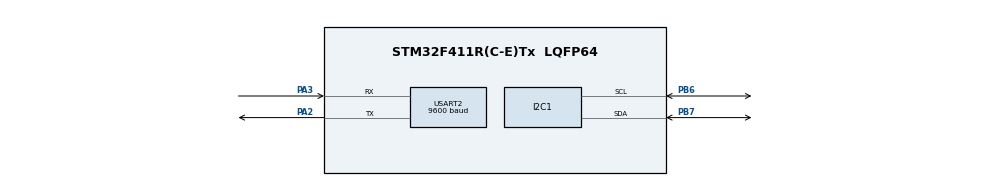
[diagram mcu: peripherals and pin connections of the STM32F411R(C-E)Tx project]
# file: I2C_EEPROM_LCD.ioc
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Mcu.Family=STM32F4
Mcu.Name=STM32F411R(C-E)Tx
Mcu.Package=LQFP64
NVIC.PriorityGroup=NVIC_PRIORITYGROUP_0
NVIC.USART2_IRQn=true\:0\:0\:false\:false\:true\:true\:true\:true
PA2.Mode=Asynchronous
PA2.Signal=USART2_TX
PA3.Mode=Asynchronous
PA3.Signal=USART2_RX
PB6.Mode=I2C
PB6.Signal=I2C1_SCL
PB7.Mode=I2C
PB7.Signal=I2C1_SDA
ProjectManager.HeapSize=0x200
ProjectManager.StackSize=0x400
ProjectManager.TargetToolchain=STM32CubeIDE
RCC.48MHZClocksFreq_Value=84000000
RCC.AHBFreq_Value=16000000
RCC.APB1CLKDivider=RCC_HCLK_DIV2
RCC.APB1Freq_Value=8000000
RCC.APB1TimFreq_Value=16000000
RCC.APB2Freq_Value=16000000
RCC.APB2TimFreq_Value=16000000
RCC.CortexFreq_Value=16000000
RCC.FLatency-AdvancedSettings=FLASH_LATENCY_0
RCC.HCLKFreq_Value=16000000
RCC.HSE_VALUE=8000000
RCC.HSI_VALUE=16000000
RCC.LSE_VALUE=32768
RCC.PLLN=336
RCC.PLLP=RCC_PLLP_DIV4
RCC.SYSCLKFreq_VALUE=16000000
RCC.VCOOutputFreq_Value=336000000
USART2.BaudRate=9600
USART2.VirtualMode=VM_ASYNC
board=NUCLEO-F411RE

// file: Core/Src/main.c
/* USER CODE BEGIN Header */
/**
  **************************
  * @file           : main.c
  * @brief          : Main program body
  **************************
  * @attention
  *
  * Copyright (c) 2022 STMicroelectronics.
  * All rights reserved.
  *
  * This software is licensed under terms that can be found in the LICENSE file
  * in the root directory of this software component.
  * If no LICENSE file comes with this software, it is provided AS-IS.
  *
  **************************
  */
/* USER CODE END Header */
#include "main.h"
#include <string.h>
#include"lcd.h"

I2C_HandleTypeDef hi2c1;

UART_HandleTypeDef huart2;

void SystemClock_Config(void);
static void MX_GPIO_Init(void);
static void MX_I2C1_Init(void);
static void MX_USART2_UART_Init(void);

uint8_t Rcvd_Data;
uint8_t Data_Buffer[8];
uint8_t i;
uint8_t USER_DATA[8] ="sandeep!";
uint8_t sentbit;

int main(void)
{

  /* MCU Configuration--------------------------------------------------------*/

  /* Reset of all peripherals, Initializes the Flash interface and the Systick. */
  HAL_Init();

  /* Configure the system clock */
  SystemClock_Config();

  /* Initialize all configured peripherals */
  MX_GPIO_Init();
  MX_I2C1_Init();
  MX_USART2_UART_Init();
  uint32_t count = 0;
  /* USER CODE BEGIN 2 */

	LCD_init();
	delay(10);

  HAL_UART_Transmit(&huart2, (uint8_t *)USER_DATA, strlen(USER_DATA), HAL_MAX_DELAY);
  /* USER CODE END 2 */
  /* Infinite loop */
  /* USER CODE BEGIN WHILE */
//  while (USER_DATA[i]!='\0')
//  {
//    /* USER CODE END WHILE */
//	  sentbit=USER_DATA[i];
//	  i++;
//	  HAL_I2C_Mem_Write(&hi2c1, 0xA0, 0, 0xFF, &sentbit, 1, 10);
//	  HAL_Delay(100);
//	  HAL_I2C_Mem_Read(&hi2c1, 0xA0, 0, 0xFF, &Rcvd_Data, 1, 10);
//	  Data_Buffer[count++] = Rcvd_Data;
//    /* USER CODE BEGIN 3 */
//  }

	while(1)
	{
		HAL_UART_Receive(&huart2, &Rcvd_Data, 1, HAL_MAX_DELAY);    //Read byte by byte

		if(Rcvd_Data == '\r')
		{
			//detect Return/Enter key
			Data_Buffer[count++] = '\r';
			break;
		}
		else
		{
			Data_Buffer[count++] = Rcvd_Data;
		}
	}

    HAL_UART_Transmit(&huart2, (uint8_t*)Data_Buffer, count, HAL_MAX_DELAY);
	i=0;
	count=0;
	while (Data_Buffer[i]!='\0')
	{
	  /* USER CODE END WHILE */
		sentbit=Data_Buffer[i];
//		i++;
		HAL_I2C_Mem_Write(&hi2c1, 0xA0, 0, 0xFF, &sentbit, 1, 10);
		HAL_Delay(100);
		HAL_I2C_Mem_Read(&hi2c1, 0xA0, 0, 0xFF, &Rcvd_Data, 1, 10);
		Data_Buffer[count++] = Rcvd_Data;
		USER_DATA[i]=Rcvd_Data;
		i=i+1;
	  /* USER CODE BEGIN 3 */
	}

	  char str[8];
	  LCD_string("AT24C32INTERFACE");
	  HAL_Delay(1000);
	  LCD_command(1);
	  LCD_string("DATA WRITE");
	  LCD_command(0xC4);
	  strcpy(str,Data_Buffer);
	  LCD_string(str);
	  HAL_Delay(1000);
	  LCD_command(1);
	  LCD_string("DATA READ");
	  LCD_command(0xC4);
	  strcpy(str,USER_DATA);
	  LCD_string(str);
	  delay(500);
  /* USER CODE END 3 */
}

void SystemClock_Config(void)
{
  RCC_OscInitTypeDef RCC_OscInitStruct = {0};
  RCC_ClkInitTypeDef RCC_ClkInitStruct = {0};

  /** Configure the main internal regulator output voltage
  */
  __HAL_RCC_PWR_CLK_ENABLE();
  __HAL_PWR_VOLTAGESCALING_CONFIG(PWR_REGULATOR_VOLTAGE_SCALE1);

  /** Initializes the RCC Oscillators according to the specified parameters
  * in the RCC_OscInitTypeDef structure.
  */
  RCC_OscInitStruct.OscillatorType = RCC_OSCILLATORTYPE_HSI;
  RCC_OscInitStruct.HSIState = RCC_HSI_ON;
  RCC_OscInitStruct.HSICalibrationValue = RCC_HSICALIBRATION_DEFAULT;
  RCC_OscInitStruct.PLL.PLLState = RCC_PLL_NONE;
  if (HAL_RCC_OscConfig(&RCC_OscInitStruct) != HAL_OK)
  {
    Error_Handler();
  }

  /** Initializes the CPU, AHB and APB buses clocks
  */
  RCC_ClkInitStruct.ClockType = RCC_CLOCKTYPE_HCLK|RCC_CLOCKTYPE_SYSCLK
                              |RCC_CLOCKTYPE_PCLK1|RCC_CLOCKTYPE_PCLK2;
  RCC_ClkInitStruct.SYSCLKSource = RCC_SYSCLKSOURCE_HSI;
  RCC_ClkInitStruct.AHBCLKDivider = RCC_SYSCLK_DIV1;
  RCC_ClkInitStruct.APB1CLKDivider = RCC_HCLK_DIV1;
  RCC_ClkInitStruct.APB2CLKDivider = RCC_HCLK_DIV1;

  if (HAL_RCC_ClockConfig(&RCC_ClkInitStruct, FLASH_LATENCY_0) != HAL_OK)
  {
    Error_Handler();
  }
}

static void MX_I2C1_Init(void)
{

  hi2c1.Instance = I2C1;
  hi2c1.Init.ClockSpeed = 100000;
  hi2c1.Init.DutyCycle = I2C_DUTYCYCLE_2;
  hi2c1.Init.OwnAddress1 = 0;
  hi2c1.Init.AddressingMode = I2C_ADDRESSINGMODE_7BIT;
  hi2c1.Init.DualAddressMode = I2C_DUALADDRESS_DISABLE;
  hi2c1.Init.OwnAddress2 = 0;
  hi2c1.Init.GeneralCallMode = I2C_GENERALCALL_DISABLE;
  hi2c1.Init.NoStretchMode = I2C_NOSTRETCH_DISABLE;
  if (HAL_I2C_Init(&hi2c1) != HAL_OK)
  {
    Error_Handler();
  }

}

static void MX_USART2_UART_Init(void)
{

  huart2.Instance = USART2;
  huart2.Init.BaudRate = 9600;
  huart2.Init.WordLength = UART_WORDLENGTH_8B;
  huart2.Init.StopBits = UART_STOPBITS_1;
  huart2.Init.Parity = UART_PARITY_NONE;
  huart2.Init.Mode = UART_MODE_TX_RX;
  huart2.Init.HwFlowCtl = UART_HWCONTROL_NONE;
  huart2.Init.OverSampling = UART_OVERSAMPLING_16;
  if (HAL_UART_Init(&huart2) != HAL_OK)
  {
    Error_Handler();
  }

}

static void MX_GPIO_Init(void)
{

  /* GPIO Ports Clock Enable */
  __HAL_RCC_GPIOA_CLK_ENABLE();
  __HAL_RCC_GPIOB_CLK_ENABLE();

}

void Error_Handler(void)
{
  __disable_irq();
  while (1)
  {
  }
}
